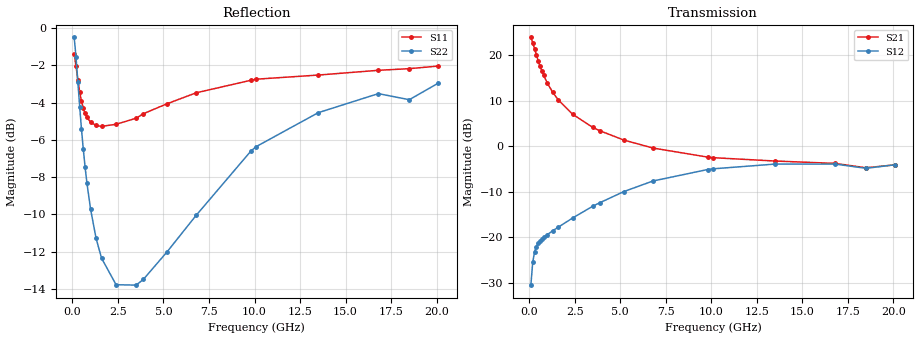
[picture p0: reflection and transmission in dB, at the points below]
!  Infineon Technologies AG
! BFR380L3 , PF131585-7, No.6, Th 09.10.01, soldered on pcb-board, measured with PP GSG850
!  Vce=2.0 V,  Ic=5.0 mA
! Common Emitter S-Parameters:  15. November 2001
#  GHz  S  MA  R  50
! f  S11  S21  S12  S22
! GHz  Mag  Ang  Mag  Ang  Mag  Ang  Mag  Ang
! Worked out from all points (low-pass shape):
!   201 points, 100 MHz to 20.1 GHz, reference 50 ohm
!   highest |S21| = 23.88 dB at 100 MHz (marker M1); lowest = -4.7 dB at 18.5 GHz (marker M2)
!   |S21| within 3 dB of the highest: start of sweep to 340.2 MHz
!   lowest |S11| = -5.3 dB at 1.6 GHz (marker M3), VSWR 3.40, Z = 14.8 - j2.99 ohm
!   |S11| at or under -10 dB: nowhere
!   |S22| runs from -14.0 to -0.5 dB; largest |S21 - S12| = 16
!   S11 on the Smith chart (normalised r, x): 100 MHz: 1.16, -3.47; 400 MHz: 0.35, -0.87; 1 GHz: 0.30, -0.26; 3.9 GHz: 0.29, +0.33; 9.8 GHz: 0.38, +1.13; 20.1 GHz: 0.97, +2.55
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0.1  0.8504 -29.2  15.63 160.5  0.02988 74.6  0.9444 -18.4
0.2  0.7907 -55.2  13.73 144.1  0.05293 62.3  0.8354 -33.5
0.3  0.7264 -77.1  11.78 131.5  0.06898 53.6  0.7176 -44.8
0.4  0.6746 -93.9  10.08 121.8  0.07889 48.0  0.6159 -53.2
0.5  0.6371 -107.6  8.69 114.2  0.08608 44.8  0.5357 -59.4
0.6  0.6096 -118.8  7.583 108.3  0.09158 42.8  0.4727 -64.3
0.7  0.5902 -128.0  6.71 103.2  0.096 41.5  0.4229 -68.1
0.8  0.5758 -135.7  5.996 99.0  0.09988 41.0  0.3835 -71.3
1  0.5591 -148.1  4.94 92.0  0.1071 40.9  0.3266 -76.4
1.3  0.548 -162.0  3.899 83.7  0.1179 42.2  0.2731 -82.6
1.6  0.545 -172.5  3.227 76.7  0.1291 44.0  0.2415 -88.1
2.4  0.5521 166.9  2.235 61.6  0.1632 47.7  0.2049 -102.2
3.5  0.5731 146.6  1.607 44.9  0.2195 49.1  0.2044 -122.1
3.9  0.5894 140.8  1.474 39.8  0.2403 48.7  0.2118 -130.9
5.2  0.6268 123.2  1.168 24.7  0.3172 43.9  0.2511 -154.0
6.8  0.6707 104.6  0.9547 10.5  0.4148 35.5  0.3147 177.6
9.799999  0.7245 79.7  0.7594 -6.6  0.5542 15.3  0.4678 138.2
10.1  0.7295 77.5  0.748 -7.7  0.5643 13.2  0.4812 134.7
13.5  0.7483 59.4  0.6875 -21.6  0.6362 -9.0  0.5931 101.8
16.8  0.7706 47.5  0.6473 -32.5  0.6365 -25.5  0.6672 78.5
18.5  0.7785 45.4  0.5799 -40.0  0.5719 -34.1  0.6426 72.5
20.1  0.7911 38.3  0.6247 -43.7  0.6252 -39.2  0.7123 61.6
